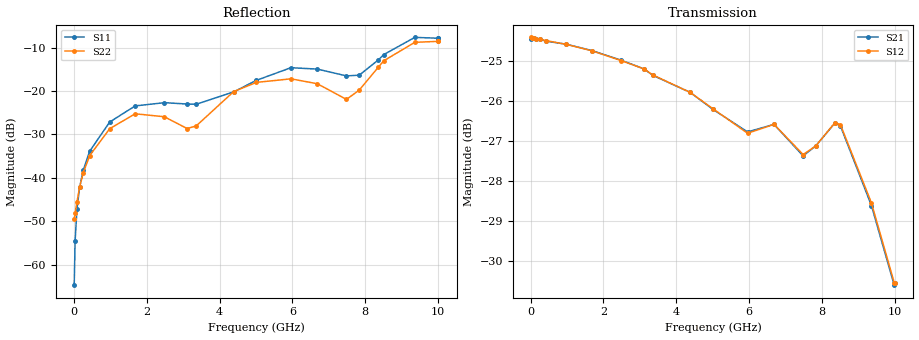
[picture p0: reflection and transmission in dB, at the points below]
! Device ID: PE43704
! Dir: z:\PE43704\PE43704_Char_1_20130516\PE43704\AMB\3p400V\23p50dB
! Serial: 14
! Insertion: A
! Impedance: 50 ohm
! Temp: Amb
! VDD: 3.400V
! Attenuation Step: 23.50dB
! IDD: 1.140243e-01mA
#  Hz  S  RI  R  50
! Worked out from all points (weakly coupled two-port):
!   401 points, 10 MHz to 10.01 GHz, reference 50 ohm
!   highest |S21| = -24.44 dB at 35 MHz (marker M1); lowest = -30.6 dB at 9.985 GHz (marker M2)
!   lowest |S11| = -64.7 dB at 10 MHz (marker M3), VSWR 1.00, Z = 50 + j0.045 ohm
!   |S11| at or under -10 dB: start of sweep to 8.731 GHz
!   |S22| runs from -49.6 to -8.5 dB; largest |S21 - S12| = 0.00068
!   S11 on the Smith chart (normalised r, x): 10 MHz: 1.00, +0.00; 7.485 GHz: 0.78, +0.15; 8.51 GHz: 0.80, +0.45; 9.36 GHz: 0.53, +0.48; 10.01 GHz: 0.46, +0.27
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1e7  0.00037 0.00045  0.0599 -0.000237  0.0601 -0.00019  0.0033 0.000387
3.5e7  0.000532 0.00179  0.06 -0.00058  0.06 -0.000655  0.00356 0.0016
8.5e7  0.000458 0.00432  0.0599 -0.00152  0.0599 -0.00148  0.00353 0.00389
1.6e8  4.16e-05 0.00782  0.0598 -0.00278  0.0598 -0.00275  0.00313 0.00726
2.6e8  -0.00183 0.0122  0.0596 -0.0044  0.0596 -0.00441  0.00144 0.0114
4.35e8  -0.00622 0.0193  0.059 -0.00723  0.0591 -0.00719  -0.00292 0.0178
9.85e8  -0.0325 0.0297  0.0568 -0.0157  0.0568 -0.0156  -0.0269 0.0252
1.685e9  -0.0658 0.0147  0.052 -0.0254  0.052 -0.0253  -0.0542 0.00759
2.485e9  -0.0731 -0.0071  0.0444 -0.0346  0.0444 -0.0345  -0.0501 -0.00679
3.11e9  -0.0705 -0.00724  0.0373 -0.0403  0.0374 -0.0402  -0.0367 0.00482
3.36e9  -0.0704 -0.00142  0.034 -0.0418  0.0341 -0.0418  -0.0372 0.0138
4.385e9  -0.0881 0.0421  0.0221 -0.0463  0.0221 -0.0463  -0.0793 0.0581
5.01e9  -0.1122 0.0709  0.0153 -0.0464  0.0153 -0.0465  -0.109 0.0626
5.96e9  -0.1602 0.0938  0.00524 -0.0455  0.00542 -0.0453  -0.1279 0.0525
6.685e9  -0.1604 0.0793  -0.000815 -0.0468  -0.000855 -0.0468  -0.1132 0.0438
7.485e9  -0.1166 0.0934  -0.00795 -0.042  -0.00781 -0.0422  -0.0502 0.0624
7.835e9  -0.0737 0.1333  -0.00984 -0.0429  -0.00982 -0.0429  -0.0354 0.0962
8.36e9  -0.0426 0.2244  -0.0192 -0.0429  -0.0191 -0.043  -0.0536 0.1807
8.51e9  -0.0456 0.2591  -0.0221 -0.041  -0.0221 -0.0412  -0.0674 0.2127
9.36e9  -0.1882 0.3696  -0.0267 -0.0257  -0.0269 -0.0259  -0.231 0.2812
9.985e9  -0.3191 0.2512  -0.0182 -0.0232  -0.0188 -0.023  -0.3531 0.1198
1.001e10  -0.3243 0.2432  -0.018 -0.0236  -0.0183 -0.0233  -0.357 0.1112
